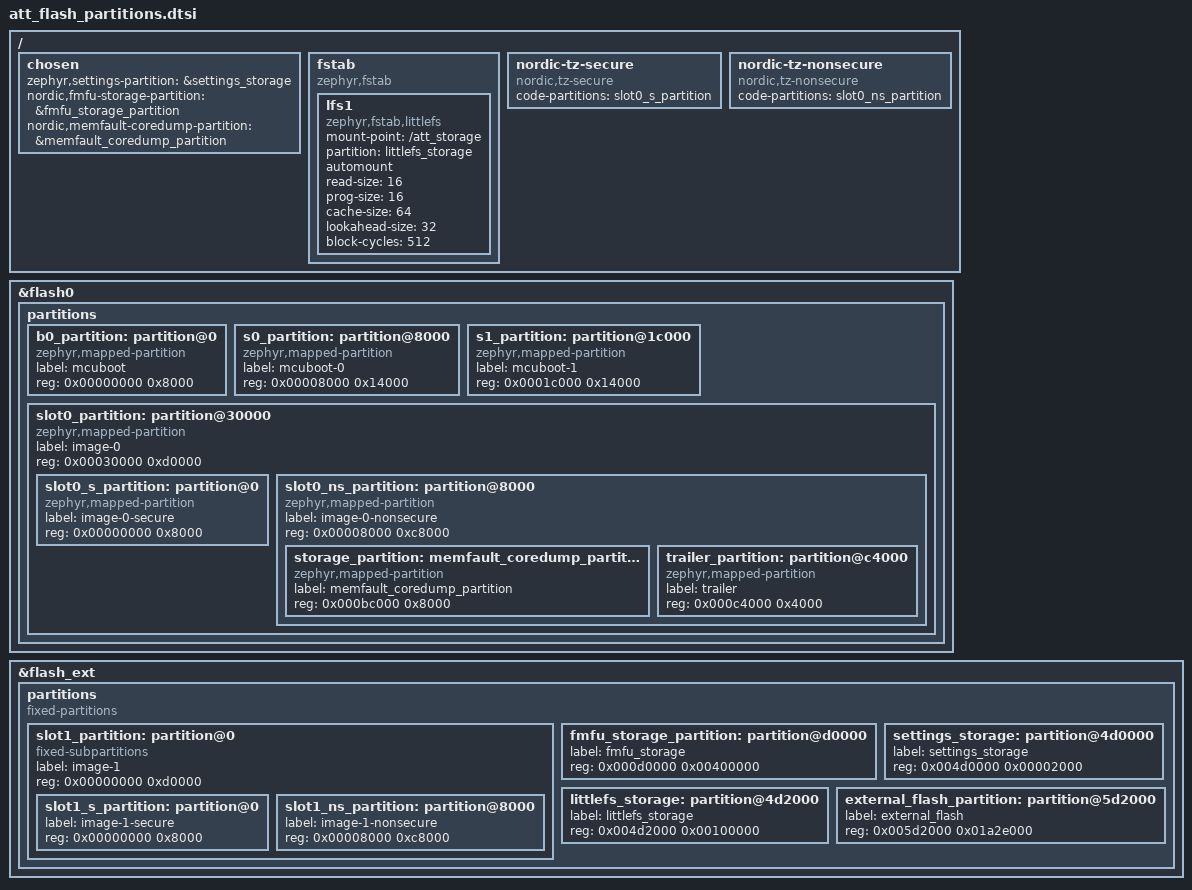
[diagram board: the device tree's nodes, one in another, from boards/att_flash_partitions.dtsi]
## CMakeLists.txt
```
#
# Copyright (c) 2024 Nordic Semiconductor ASA
#
# SPDX-License-Identifier: LicenseRef-Nordic-5-Clause
#

cmake_minimum_required(VERSION 3.20.0)

# Must run before find_package(Zephyr), which reads the Kconfig tree the patches change.
# sysbuild builds apply them earlier, from sysbuild.cmake.
include(${CMAKE_CURRENT_LIST_DIR}/../cmake/apply_sdk_patches.cmake)

find_package(Zephyr REQUIRED HINTS $ENV{ZEPHYR_BASE})
project("Asset Tracker Template")

# Include files that are common for all modules
zephyr_include_directories(src/common)
zephyr_include_directories(memfault/config)

# Add main application source
target_sources(app PRIVATE
	src/main.c
	src/common/app_watchdog.c
)

target_sources_ifdef(CONFIG_APP_NRF9251_HSFLL120_KEEPALIVE app PRIVATE
	src/common/nrf9251_hsfll120_keepalive.c
)

# Module source folders
add_subdirectory(src/modules/network)
add_subdirectory(src/cbor)
add_subdirectory(memfault)

# Optional modules
add_subdirectory_ifdef(CONFIG_APP_BUTTON src/modules/button)
add_subdirectory_ifdef(CONFIG_APP_POWER src/modules/power)
add_subdirectory_ifdef(CONFIG_APP_ENVIRONMENTAL src/modules/environmental)
add_subdirectory_ifdef(CONFIG_APP_LED src/modules/led)
add_subdirectory_ifdef(CONFIG_APP_LOCATION src/modules/location)
add_subdirectory_ifdef(CONFIG_APP_CLOUD src/modules/cloud)
add_subdirectory_ifdef(CONFIG_APP_FOTA src/modules/fota)
add_subdirectory_ifdef(CONFIG_APP_STORAGE src/modules/storage)
add_subdirectory_ifdef(CONFIG_APP_UART_POWER_CONTROL src/modules/uart_power_control)
```

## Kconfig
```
#
# Copyright (c) 2024 Nordic Semiconductor ASA
#
# SPDX-License-Identifier: LicenseRef-Nordic-5-Clause
#

menu "Asset Tracker Template"

rsource "src/Kconfig.main"
rsource "src/modules/power/Kconfig.power"
rsource "src/modules/uart_power_control/Kconfig.uart_power_control"
rsource "src/modules/network/Kconfig.network"
rsource "src/modules/cloud/Kconfig.cloud"
rsource "src/modules/location/Kconfig.location"
rsource "src/modules/led/Kconfig.led"
rsource "src/modules/fota/Kconfig.fota"
rsource "src/modules/environmental/Kconfig.environmental"
rsource "src/modules/button/Kconfig.button"
rsource "src/modules/storage/Kconfig.storage"
rsource "memfault/Kconfig.memfault"

endmenu

menu "Zephyr Kernel"
source "Kconfig.zephyr"
endmenu
```

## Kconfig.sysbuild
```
#
# Copyright (c) 2025 Nordic Semiconductor ASA
#
# SPDX-License-Identifier: LicenseRef-Nordic-5-Clause
#

choice BOOTLOADER
	default BOOTLOADER_MCUBOOT if !BOARD_NATIVE_SIM
endchoice

config NCS_MCUBOOT_LOAD_PERIPHCONF
	default y if BOARD_NRF9251DK_NRF9251_CPUAPP

config SECURE_BOOT_APPCORE
	default y if BOARD_NRF9151DK_NRF9151_NS

# Merge the hex files as a single file for easier flashing with external tools.
config MERGED_HEX_FILES
	default y

# Shared NSIB (b0) signing key for all ATT sysbuild targets. Sysbuild signs images with this
# key; b0 verifies them. Without this, sysbuild autogenerates a new debug key on each pristine
# build. Not for production.
config SECURE_BOOT_SIGNING_KEY_FILE
	default "$(ZEPHYR_NRF_MODULE_DIR)/boards/nordic/thingy91x/nsib_signing_key.pem"

config WIFI_NRF70
	default y if BOARD_THINGY91X_NRF9151_NS

choice WIFI_NRF70_OPER_MODES
	default WIFI_NRF70_SCAN_ONLY if BOARD_THINGY91X_NRF9151_NS
endchoice

source "${ZEPHYR_BASE}/share/sysbuild/Kconfig"
```

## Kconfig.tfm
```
#
# Copyright (c) 2025 Nordic Semiconductor ASA
#
# SPDX-License-Identifier: LicenseRef-Nordic-5-Clause
#

config PM_PARTITION_SIZE_TFM_SRAM
	hex
	default 0x4000
```

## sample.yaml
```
sample:
  name: Asset Tracker Template
  description: Modular, event-driven application framework for nRF91-based asset tracking devices.
tests:
  asset_tracker_template.app:
    sysbuild: true
    build_only: true
    integration_platforms:
      - thingy91x/nrf9151/ns
      - nrf9151dk/nrf9151/ns
      - nrf9251dk/nrf9251/cpuapp
    platform_allow:
      - thingy91x/nrf9151/ns
      - nrf9151dk/nrf9151/ns
      - nrf9251dk/nrf9251/cpuapp
    tags:
      - ci_build
      - sysbuild
```

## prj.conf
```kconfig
#
# Copyright (c) 2024 Nordic Semiconductor ASA
#
# SPDX-License-Identifier: LicenseRef-Nordic-5-Clause
#

CONFIG_NCS_APPLICATION_BOOT_BANNER_STRING="Asset Tracker Template"
CONFIG_NCS_SAMPLES_DEFAULTS=y
CONFIG_WARN_EXPERIMENTAL=n
CONFIG_RESET_ON_FATAL_ERROR=y
CONFIG_LOG_MODE_DEFERRED=y
CONFIG_LOG_BUFFER_SIZE=2048
CONFIG_LOG_PROCESS_THREAD_STACK_SIZE=1280
CONFIG_ZVFS_OPEN_MAX=20
CONFIG_PWM=y

# Heap and stacks
CONFIG_MAIN_STACK_SIZE=2560
# Extended AT host/monitor stack/heap sizes since some nrf_cloud credentials are longer than 1024 bytes.
CONFIG_AT_MONITOR_HEAP_SIZE=2176
CONFIG_HEAP_MEM_POOL_SIZE=12288
CONFIG_HEAP_MEM_POOL_IGNORE_MIN=y
CONFIG_SYSTEM_WORKQUEUE_STACK_SIZE=1408

# Enable Networking
CONFIG_NETWORKING=y
CONFIG_NET_SOCKETS=y
CONFIG_NET_IPV4=y

# Enable Link Controller modules
CONFIG_LTE_LINK_CONTROL=y
CONFIG_LTE_LC_PDN_MODULE=y
CONFIG_LTE_LC_PSM_MODULE=y
CONFIG_LTE_LC_EDRX_MODULE=y
CONFIG_LTE_LC_MODEM_SLEEP_NOTIFICATIONS=y

# Set data profile to ultra-low power
CONFIG_LTE_LC_DATA_PROFILE_MODULE=y
CONFIG_LTE_DATA_PROFILE_INIT_ULTRA_LOW_POWER=y

# Enable PSM (Power Saving Mode)
CONFIG_LTE_LC_WORKQUEUE_STACK_SIZE=2048
CONFIG_LTE_PSM_REQ=y
CONFIG_LTE_PROPRIETARY_PSM_REQ=y
CONFIG_LTE_PSM_REQ_FORMAT_SECONDS=y
# Set Requested TAU to a large value. If the network does not support this value,
# it will typically use the largest supported value. This value should be larger
# than the default update interval (1 hour).
CONFIG_LTE_PSM_REQ_RPTAU_SECONDS=7200

# Set the PSM Requested Active Time to a low number. Since we are constantly polling for
# downlink data, there is no need for prolonged active paging after the RRC connection release.
CONFIG_LTE_PSM_REQ_RAT_SECONDS=6

# Enable eDRX (Extended Discontinuous Reception)
CONFIG_LTE_EDRX_REQ=y
# "0000" is 5.12 s
CONFIG_LTE_EDRX_REQ_VALUE_LTE_M="0000"
CONFIG_LTE_EDRX_REQ_VALUE_NBIOT="0000"

# Modem library
CONFIG_NRF_MODEM_LIB=y
CONFIG_NRF_MODEM_LIB_FAULT_STRERROR=y
CONFIG_NRF_MODEM_LIB_ON_FAULT_APPLICATION_SPECIFIC=y

# Shell
CONFIG_UART_INTERRUPT_DRIVEN=y
CONFIG_SHELL=y
CONFIG_SHELL_WILDCARD=n
CONFIG_SHELL_STACK_SIZE=2560
CONFIG_SHELL_CMD_BUFF_SIZE=2048
CONFIG_SHELL_BACKEND_SERIAL_RX_RING_BUFFER_SIZE=2048
CONFIG_AT_SHELL=y
CONFIG_PM_DEVICE_SHELL=y
# Disable unused shell modules
CONFIG_LTE_SHELL=n
CONFIG_DEVICE_SHELL=n
CONFIG_DATE_SHELL=n
CONFIG_DEVMEM_SHELL=n
CONFIG_APP_VERSION_SHELL=n

# nRF Cloud
CONFIG_NRF_CLOUD=y
CONFIG_NRF_CLOUD_COAP=y
CONFIG_NRF_CLOUD_CHECK_CREDENTIALS=y
CONFIG_NRF_CLOUD_CREDENTIALS_MGMT_MODEM=y
CONFIG_NRF_CLOUD_COAP_MAX_RETRIES=3
CONFIG_NRF_CLOUD_COAP_DISCONNECT_ON_FAILED_REQUEST=y
CONFIG_NRF_CLOUD_COAP_MAX_USER_OPTIONS=2
CONFIG_NRF_CLOUD_PRINT_DETAILS=n
CONFIG_NRF_CLOUD_SEND_SHADOW_INFO_ON_CONNECT=n

# Modem key management and JWT for nRF Cloud authentication
CONFIG_MODEM_KEY_MGMT=y
CONFIG_MODEM_JWT=y

# On initial connection to the cloud, add info sections to the shadow
CONFIG_MODEM_INFO=y
CONFIG_MODEM_INFO_ADD_DEVICE=y
CONFIG_NRF_CLOUD_SEND_DEVICE_STATUS=y
CONFIG_NRF_CLOUD_SEND_DEVICE_INFO_BOOTLOADER_VERSION=y
CONFIG_NRF_CLOUD_SEND_DEVICE_STATUS_NETWORK=y
CONFIG_NRF_CLOUD_SEND_DEVICE_STATUS_SIM=y
CONFIG_NRF_CLOUD_SEND_SERVICE_INFO_FOTA=y

# MCUBOOT - Needed by FOTA
CONFIG_BOOTLOADER_MCUBOOT=y
CONFIG_IMG_MANAGER=y
CONFIG_MCUBOOT_IMG_MANAGER=y

# Date Time lib - Used by PGPS and main application
CONFIG_DATE_TIME=y
CONFIG_DATE_TIME_LOG_LEVEL_ERR=y

CONFIG_SETTINGS=y
CONFIG_SETTINGS_FCB=y
CONFIG_FCB=y

# Downloader - used by FOTAS
CONFIG_DOWNLOADER=y
CONFIG_DOWNLOADER_STACK_SIZE=2000
CONFIG_DOWNLOADER_MAX_FILENAME_SIZE=400
CONFIG_DOWNLOADER_TRANSPORT_HTTP=n
CONFIG_DOWNLOADER_TRANSPORT_COAP=y

# Flash - Used by FOTA
CONFIG_FLASH=y
CONFIG_FLASH_PAGE_LAYOUT=y
CONFIG_FLASH_MAP=y
CONFIG_STREAM_FLASH=y
CONFIG_MPU_ALLOW_FLASH_WRITE=y
CONFIG_NRF_CLOUD_FOTA_POLL=y
CONFIG_NRF_CLOUD_FOTA_DOWNLOAD_FRAGMENT_SIZE=1900
CONFIG_NRF_CLOUD_FOTA_POLL_JOB_CHECK_PROGRESS_THRESHOLD=10
CONFIG_NRF_CLOUD_COAP_DOWNLOADS=y
CONFIG_FOTA_DOWNLOAD=y
CONFIG_FOTA_DOWNLOAD_PROGRESS_EVT=y
CONFIG_FOTA_DL_TIMEOUT_MIN=60
CONFIG_FOTA_SOCKET_RETRIES=5
CONFIG_DFU_TARGET=y

# Memfault
CONFIG_MEMFAULT=y

CONFIG_MEMFAULT_NCS_FW_VERSION_STATIC=y
CONFIG_MEMFAULT_LOGGING_ENABLE=y
CONFIG_MEMFAULT_LOGGING_RAM_SIZE=4096
CONFIG_MEMFAULT_EVENT_STORAGE_SIZE=2048
# Coredump is stored in the dedicated memfault_coredump_partition (32 KiB) that
# lives inside slot0 between the app image and MCUboot's reserved tail. See
# app/boards/att_flash_partitions.dtsi for the layout rationale.
CONFIG_MEMFAULT_NCS_INTERNAL_FLASH_BACKED_COREDUMP=y
CONFIG_MEMFAULT_COREDUMP_STACK_SIZE_TO_COLLECT=1024
CONFIG_MEMFAULT_NCS_POST_COREDUMP_ON_NETWORK_CONNECTED=y

# Upload Memfault data via nRF Cloud CoAP transport.
CONFIG_MEMFAULT_USE_NRF_CLOUD_COAP=y
CONFIG_MEMFAULT_HTTP_ENABLE=n

# Enable a minimal set of Memfault metrics.
CONFIG_MEMFAULT_NCS_LTE_METRICS=y
CONFIG_MEMFAULT_NCS_LOCATION_METRICS=y
CONFIG_MEMFAULT_NCS_STACK_METRICS=n
CONFIG_MEMFAULT_FS_BYTES_FREE_METRIC=n

# Memfault depends on POSIX, disable unneeded POSIX features
CONFIG_POSIX_FILE_SYSTEM=n

# COAP client
# Disable CoAP client retransmissions to rely on nRF Cloud CoAP transport layer retries
# (CONFIG_NRF_CLOUD_COAP_MAX_RETRIES). Multiple retransmission layers scales poorly.
CONFIG_COAP_MAX_RETRANSMIT=1
CONFIG_COAP_INIT_ACK_TIMEOUT_MS=5000
# Set the CoAP client thread to same priority as other modules
CONFIG_COAP_CLIENT_THREAD_PRIORITY=14
CONFIG_COAP_CLIENT_BLOCK_SIZE=1024
CONFIG_COAP_CLIENT_MESSAGE_SIZE=1024
CONFIG_COAP_CLIENT_STACK_SIZE=1280
CONFIG_COAP_EXTENDED_OPTIONS_LEN_VALUE=192
CONFIG_COAP_CLIENT_MAX_PATH_LENGTH=128
CONFIG_COAP_CLIENT_MAX_EXTRA_OPTIONS=3

# Needed for processing floats
CONFIG_PICOLIBC=y
CONFIG_FPU=y

# Zbus
CONFIG_ZBUS=y
CONFIG_ZBUS_MSG_SUBSCRIBER=y
CONFIG_ZBUS_MSG_SUBSCRIBER_NET_BUF_POOL_SIZE=64
CONFIG_ZBUS_CHANNEL_NAME=y

# Zephyr State Machine Framework
CONFIG_SMF=y
CONFIG_SMF_ANCESTOR_SUPPORT=y
CONFIG_SMF_INITIAL_TRANSITION=y

# Location
CONFIG_LOCATION=y
CONFIG_LOCATION_DATA_DETAILS=y
CONFIG_LOCATION_METHOD_GNSS=y
CONFIG_LOCATION_METHOD_CELLULAR=y
CONFIG_LOCATION_SERVICE_EXTERNAL=y
CONFIG_LOCATION_REQUEST_DEFAULT_GNSS_TIMEOUT=60000
CONFIG_LOCATION_REQUEST_DEFAULT_CELLULAR_TIMEOUT=30000
CONFIG_LOCATION_REQUEST_DEFAULT_TIMEOUT=120000
CONFIG_LOCATION_REQUEST_DEFAULT_CELLULAR_CELL_COUNT=3
CONFIG_LOCATION_REQUEST_DEFAULT_GNSS_ACCURACY_LOW=y
CONFIG_LOCATION_REQUEST_DEFAULT_GNSS_VISIBILITY_DETECTION=y
CONFIG_LTE_NETWORK_MODE_LTE_M_NBIOT_GPS=y
CONFIG_NRF_CLOUD_AGNSS=y
# These two must be in sync
CONFIG_APP_LOCATION_NEIGHBOR_CELLS_MAX=8
CONFIG_LTE_NEIGHBOR_CELLS_MAX=8

# Extra Logging
CONFIG_APP_FOTA_LOG_LEVEL_DBG=y
CONFIG_APP_LOCATION_LOG_LEVEL_DBG=y
CONFIG_APP_CLOUD_LOG_LEVEL_DBG=y
CONFIG_APP_NETWORK_LOG_LEVEL_DBG=y
CONFIG_APP_LOG_LEVEL_DBG=y
CONFIG_APP_STORAGE_LOG_LEVEL_DBG=y
CONFIG_APP_BUTTON_LOG_LEVEL_DBG=y

# Task Watchdog
CONFIG_WATCHDOG=y
CONFIG_TASK_WDT=y
CONFIG_TASK_WDT_HW_FALLBACK=y
CONFIG_TASK_WDT_CHANNELS=8
CONFIG_TASK_WDT_MIN_TIMEOUT=10000

# Device power management
CONFIG_PM_DEVICE=y
CONFIG_PM_DEVICE_RUNTIME=n

# nRF Cloud Provisioning
CONFIG_MODEM_ATTEST_TOKEN=y
CONFIG_NRF_PROVISIONING=y
CONFIG_NRF_PROVISIONING_CBOR_RECORDS=5
CONFIG_NRF_PROVISIONING_COAP=y
CONFIG_NRF_PROVISIONING_CODEC=y
CONFIG_NRF_PROVISIONING_CBOR=y
CONFIG_NRF_PROVISIONING_WITH_CERT=y
CONFIG_NRF_PROVISIONING_RX_BUF_SZ=2560
CONFIG_NRF_PROVISIONING_TX_BUF_SZ=2048
CONFIG_NRF_PROVISIONING_STACK_SIZE=3072
CONFIG_NRF_PROVISIONING_CODEC_AT_CMD_LEN=2048
CONFIG_NRF_PROVISIONING_CODEC_RX_SZ_START=1024
```

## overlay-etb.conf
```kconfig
#
# Copyright (c) 2024 Nordic Semiconductor ASA
#
# SPDX-License-Identifier: LicenseRef-Nordic-5-Clause
#

# ETB tracing
CONFIG_ETB_TRACE=y
CONFIG_ETB_TRACE_LOW_POWER=y
CONFIG_ETB_TRACE_LOW_POWER_MIN_IDLE_TIME_MS=1
CONFIG_MEMFAULT_NCS_ETB_CAPTURE=y
# Reduce logging to avoid filling up ETB with data not related to the crash
CONFIG_FAULT_DUMP=0
CONFIG_KERNEL_LOG_LEVEL_OFF=y
```

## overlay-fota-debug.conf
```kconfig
#
# Copyright (c) 2026 Nordic Semiconductor ASA
#
# SPDX-License-Identifier: LicenseRef-Nordic-5-Clause
#

# Debug logging for the FOTA and Memfault OTA path.
# Usage: west build ... -- -DEXTRA_CONF_FILE=overlay-fota-debug.conf

# Memfault SDK (module "mflt", includes the OTA query and override backend)
CONFIG_MEMFAULT_LOG_LEVEL_DBG=y

# nRF Cloud job handling, download and CoAP transport
CONFIG_NRF_CLOUD_FOTA_POLL_LOG_LEVEL_DBG=y
CONFIG_NRF_CLOUD_LOG_LEVEL_DBG=y
CONFIG_NRF_CLOUD_COAP_LOG_LEVEL_DBG=y

# Download and DFU target (image type detection, slot handling)
CONFIG_FOTA_DOWNLOAD_LOG_LEVEL_DBG=y
CONFIG_DFU_TARGET_LOG_LEVEL_DBG=y
CONFIG_DOWNLOADER_LOG_LEVEL_DBG=y

# Log buffering: debug output from the download path is bursty
CONFIG_LOG_BUFFER_SIZE=8192
```

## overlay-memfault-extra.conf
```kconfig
#
# Copyright (c) 2026 Nordic Semiconductor
#
# SPDX-License-Identifier: LicenseRef-Nordic-5-Clause
#

# Enable richer diagnostics for Memfault
CONFIG_MEMFAULT_HEAP_STATS=y
CONFIG_MEMFAULT_EVENT_STORAGE_SIZE=4096
CONFIG_MEMFAULT_LOGGING_RAM_SIZE=3584
CONFIG_PM_PARTITION_SIZE_MEMFAULT_STORAGE=0x2A000
CONFIG_MEMFAULT_COREDUMP_FULL_THREAD_STACKS=y
CONFIG_MEMFAULT_COREDUMP_COLLECT_BSS_REGIONS=y
```

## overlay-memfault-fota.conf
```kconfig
# FOTA support
CONFIG_MEMFAULT_FOTA=y
CONFIG_DOWNLOADER_MAX_FILENAME_SIZE=400
CONFIG_DOWNLOADER_TRANSPORT_COAP=y
CONFIG_NRF_CLOUD_COAP_DOWNLOADS=y
CONFIG_APP_FOTA_TYPE_MEMFAULT=y
```

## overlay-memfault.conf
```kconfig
#
# Copyright (c) 2025 Nordic Semiconductor
#
# SPDX-License-Identifier: LicenseRef-Nordic-5-Clause
#

CONFIG_MEMFAULT=y
CONFIG_MEMFAULT_HEAP_STATS=y
CONFIG_MEMFAULT_LOGGING_ENABLE=y
CONFIG_MEMFAULT_LOGGING_RAM_SIZE=3584
CONFIG_MEMFAULT_FS_BYTES_FREE_METRIC=n
CONFIG_MEMFAULT_COREDUMP_FULL_THREAD_STACKS=y
CONFIG_MEMFAULT_EVENT_STORAGE_SIZE=4096
CONFIG_MEMFAULT_COREDUMP_COLLECT_BSS_REGIONS=y

# Use CoAP for Memfault data transport
CONFIG_MEMFAULT_USE_NRF_CLOUD_COAP=y
CONFIG_MEMFAULT_HTTP_ENABLE=n
CONFIG_NRF_CLOUD_COAP_MAX_USER_OPTIONS=2
CONFIG_COAP_CLIENT_MAX_EXTRA_OPTIONS=3

# Increase max post size to maximum allowable to improve upload efficiency.
# This value is calculated from:
# (COAP_CLIENT_MESSAGE_SIZE + COAP_CLIENT_MESSAGE_HEADER_SIZE - 100B options overhead).
CONFIG_MEMFAULT_COAP_MAX_POST_SIZE=972

# Set max number of messages to send in one batch to max allowable to support
# uploading flash-backed coredumps and modem traces in one upload attempt.
#
# Note: Sending all available data will not block other tasks since upload
# always occurs in a dedicated thread (either via mflt_lte_coredump_thread when
# CONFIG_MEMFAULT_NCS_POST_COREDUMP_ON_NETWORK_CONNECTED is enabled or via
# CONFIG_MEMFAULT_PERIODIC_UPLOAD_USE_DEDICATED_WORKQUEUE which is default y).
CONFIG_MEMFAULT_COAP_MAX_MESSAGES_TO_SEND=10000

# Certificate management - use Zephyr TLS credentials for native TLS on nRF54LM20
# (not modem-offloaded TLS)
CONFIG_MEMFAULT_ROOT_CERT_STORAGE_TLS_CREDENTIAL_STORAGE=y
# Disable modem key management certificate provisioning since we use native TLS
CONFIG_MEMFAULT_NCS_PROVISION_CERTIFICATES=n

# Memfault NCS integration
CONFIG_MEMFAULT_NCS_LTE_METRICS=y
CONFIG_MEMFAULT_NCS_STACK_METRICS=y
CONFIG_MEMFAULT_NCS_POST_COREDUMP_ON_NETWORK_CONNECTED=y
CONFIG_MEMFAULT_NCS_POST_COREDUMP_RETRIES_MAX=10
CONFIG_MEMFAULT_NCS_FW_TYPE="att"

# Ensure Memfault device id matches nRF Cloud client id
CONFIG_MEMFAULT_NCS_DEVICE_ID_HW_ID=y
CONFIG_HW_ID_LIBRARY_SOURCE_UUID=y

# Memfault depends on POSIX, disable unneeded POSIX features
CONFIG_POSIX_FILE_SYSTEM=n
CONFIG_MEMFAULT_LOG_LEVEL_DBG=y
CONFIG_MEMFAULT_NCS_LOG_LEVEL_DBG=y
```

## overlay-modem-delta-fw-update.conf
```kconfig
#
# Copyright (c) 2026 Nordic Semiconductor ASA
#
# SPDX-License-Identifier: LicenseRef-Nordic-5-Clause
#
# Overlay for enabling delta modem FOTA.
# See https://docs.nrfcloud.com/docs/mcu/nrf-modem-fota for full setup instructions.

CONFIG_MEMFAULT_FOTA_MODEM_UPDATE=y
CONFIG_MEMFAULT_FOTA_MODEM_PROJECT_KEY="YOUR_MODEM_PROJECT_KEY"
```

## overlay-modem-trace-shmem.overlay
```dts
/*
 * Copyright (c) 2026 Nordic Semiconductor ASA
 *
 * SPDX-License-Identifier: LicenseRef-Nordic-5-Clause
 */

&sram0_ns_modem {
	reg = <0x0 0x64e8>;
	ranges = <0x0 0x0 0x64e8>;

	cpucell_cpuapp_ipc_shm_trace: sram0_ns_modem@24e8 {
		reg = <0x24e8 0x4000>;
	};
};

/delete-node/ &sram0_ns_app;

&sram0_ns {
	sram0_ns_app: sram0_ns@64e8 {
		reg = <0x64e8 0x37b18>;
	};
};
```

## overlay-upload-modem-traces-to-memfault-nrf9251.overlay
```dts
/*
 * Copyright (c) 2026 Nordic Semiconductor ASA
 *
 * SPDX-License-Identifier: LicenseRef-Nordic-5-Clause
 */

/*
 * nRF9251 counterpart of overlay-upload-modem-traces-to-memfault.overlay. Pair with
 * overlay-upload-modem-traces-to-memfault.conf.
 *
 * The trace UART and shared memory region mirror the nrf92-modem-trace-uart snippet
 * (nrf/snippets/nrf92-modem-trace-uart).
 */

/* Used by the modem_trace dump_uart shell command. */
&uart132 {
	status = "okay";
	current-speed = <1000000>;
	memory-regions = <&cpuapp_dma_region>;
};

/ {
	chosen {
		nordic,modem-trace-uart = &uart132;
	};
};

/delete-node/ &cpuapp_cpucell_ipc_shm_ctrl;
/delete-node/ &cpuapp_cpucell_ipc_shm_heap;
/delete-node/ &cpucell_cpuapp_ipc_shm_heap;

/* Reduce size of application RAM to make room for trace. */
&cpuapp_ram0x_sram {
	reg = <0x2f000000 DT_SIZE_K(332)>;
	ranges = <0x0 0x2f000000 0x53000>;
};

&cpuapp_cpucell_ram0x_region {
	/* Move IPC shared memory and add trace region. */
	cpuapp_cpucell_ipc_shm_ctrl: memory@3000 {
		reg = <0x3000 DT_SIZE_K(4)>;
	};

	cpuapp_cpucell_ipc_shm_heap: memory@4000 {
		reg = <0x4000 DT_SIZE_K(16)>;
	};

	cpucell_cpuapp_ipc_shm_heap: memory@8000 {
		reg = <0x8000 DT_SIZE_K(16)>;
	};

	cpucell_cpuapp_ipc_shm_trace: memory@c000 {
		reg = <0xc000 DT_SIZE_K(16)>;
	};
};

/delete-node/ &external_flash_partition;

&flash_ext {
	partitions {
		modem_trace: partition@500000 {
			label = "modem_trace";
			reg = <0x00500000 0x000ff000>;
		};

		external_flash_partition: partition@5ff000 {
			label = "external_flash";
			reg = <0x005ff000 0x01a01000>;
		};
	};
};
```

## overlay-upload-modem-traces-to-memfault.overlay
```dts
/*
 * Copyright (c) 2026 Nordic Semiconductor ASA
 *
 * SPDX-License-Identifier: LicenseRef-Nordic-5-Clause
 */

&sram0_ns_modem {
	reg = <0x0 0x8800>;
	ranges = <0x0 0x0 0x8800>;

	cpucell_cpuapp_ipc_shm_trace: sram0_ns_modem@4800 {
		reg = <0x4800 0x4000>;
	};
};

/delete-node/ &sram0_ns_app;

&sram0_ns {
	sram0_ns_app: sram0_ns@8800 {
		reg = <0x8800 0x35800>;
	};
};

/delete-node/ &external_flash_partition;

&flash_ext {
	partitions {
		modem_trace: partition@5d2000 {
			label = "modem_trace";
			reg = <0x005d2000 0x000ff000>;
		};

		external_flash_partition: partition@6d1000 {
			label = "external_flash";
			reg = <0x006d1000 0x0192f000>;
		};
	};
};
```

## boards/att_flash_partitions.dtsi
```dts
/*
 * Copyright (c) 2026 Nordic Semiconductor ASA
 *
 * SPDX-License-Identifier: LicenseRef-Nordic-5-Clause
 *
 * Flash layout (flash0, 1 MiB internal):
 * 0x0000_0000  b0_partition                  ( 32 KiB)  immutable bootloader
 * 0x0000_8000  s0_partition                  ( 80 KiB)  primary MCUboot
 * 0x0001_c000  s1_partition                  ( 80 KiB)  secondary MCUboot
 * 0x0003_0000  slot0_partition (image-0)     (832 KiB)
 *   0x0003_0000  slot0_s_partition           ( 32 KiB)  TF-M secure
 *   0x0003_8000  slot0_ns_partition          (800 KiB)  Zephyr/app non-secure
 *     0x000f_4000  memfault_coredump         ( 32 KiB)  coredump (sub-partition)
 *     0x000f_c000  trailer (magic + swap)    ( 16 KiB)  MCUboot swap-status region (sub-partition)
 *
 * Flash layout (flash_ext, 32 MiB external):
 * 0x0000_0000  slot1_partition (image-1)     (832 KiB)  matches slot0 for MCUboot swap-move
 *   0x0000_0000  slot1_s_partition           ( 32 KiB) TF-M secure
 *   0x0000_8000  slot1_ns_partition          (800 KiB) Zephyr/app non-secure
 *   0x000c_8000  ( reserved, unused )        ( 32 KiB) no coredump on secondary
 * 0x000d_0000  fmfu_storage_partition        (  4 MiB) FMFU storage
 * 0x004d_0000  settings_storage              (  8 KiB) Zephyr settings
 * 0x004d_2000  littlefs_storage              (  1 MiB) LittleFS storage
 * 0x005d_2000  external_flash_partition      (~26.2 MiB) free space
 */



/ {
	chosen {
		zephyr,settings-partition = &settings_storage;
		nordic,fmfu-storage-partition = &fmfu_storage_partition;
		nordic,memfault-coredump-partition = &memfault_coredump_partition;
	};

	fstab {
		compatible = "zephyr,fstab";
		lfs1: lfs1 {
			compatible = "zephyr,fstab,littlefs";
			mount-point = "/att_storage";
			partition = <&littlefs_storage>;
			automount;
			read-size = <16>;
			prog-size = <16>;
			cache-size = <64>;
			lookahead-size = <32>;
			block-cycles = <512>;
		};
	};

	/* TrustZone partitioning for this layout. The SoC defaults reference the TF-M
	 * storage partitions, which this layout does not have.
	 */
	/delete-node/ nordic-tz-secure;
	/delete-node/ nordic-tz-nonsecure;

	nordic-tz-secure {
		compatible = "nordic,tz-secure";
		code-partitions = <&slot0_s_partition>;
	};

	nordic-tz-nonsecure {
		compatible = "nordic,tz-nonsecure";
		code-partitions = <&slot0_ns_partition>;
	};
};

/delete-node/ &slot0_partition;

/delete-node/ &storage_partition;

&flash0 {
	partitions {
		ranges;
		#address-cells = <1>;
		#size-cells = <1>;

		b0_partition: partition@0 {
			compatible = "zephyr,mapped-partition";
			label = "mcuboot";
			reg = <0x00000000 0x8000>;
		};

		s0_partition: partition@8000 {
			compatible = "zephyr,mapped-partition";
			label = "mcuboot-0";
			reg = <0x00008000 0x14000>;
		};

		s1_partition: partition@1c000 {
			compatible = "zephyr,mapped-partition";
			label = "mcuboot-1";
			reg = <0x0001c000 0x14000>;
		};

		slot0_partition: partition@30000 {
			compatible = "zephyr,mapped-partition";
			label = "image-0";
			reg = <0x00030000 0xd0000>;
			ranges = <0x0 0x00030000 0xd0000>;
			#address-cells = <1>;
			#size-cells = <1>;

			slot0_s_partition: partition@0 {
				compatible = "zephyr,mapped-partition";
				label = "image-0-secure";
				reg = <0x00000000 0x8000>;
			};

			slot0_ns_partition: partition@8000 {
				compatible = "zephyr,mapped-partition";
				label = "image-0-nonsecure";
				reg = <0x00008000 0xc8000>;
				ranges = <0x0 0x00008000 0xc8000>;
				#address-cells = <1>;
				#size-cells = <1>;

				storage_partition: memfault_coredump_partition: partition@bc000 {
					compatible = "zephyr,mapped-partition";
					label = "memfault_coredump_partition";
					reg = <0x000bc000 0x8000>;
				};

				/*
				 * MCUboot computes its trailer offset from the end of
				 * slot0_partition (flash_area size - boot_trailer_sz()); it
				 * never reads this node. This partition exists purely to mark
				 * that region as reserved in the layout. 16 KiB is reserved for
				   the trailer, actual size may be smaller (typically ~ 6 KiB).
				 */
				trailer_partition: partition@c4000 {
					compatible = "zephyr,mapped-partition";
					label = "trailer";
					reg = <0x000c4000 0x4000>;
				};
			};
		};
	};
};

&flash_ext {
	status = "okay";

	partitions {
		compatible = "fixed-partitions";
		#address-cells = <1>;
		#size-cells = <1>;

		slot1_partition: partition@0 {
			compatible = "fixed-subpartitions";
			label = "image-1";
			reg = <0x00000000 0xd0000>;
			ranges = <0x0 0x00000 0xd0000>;
			#address-cells = <1>;
			#size-cells = <1>;

			slot1_s_partition: partition@0 {
				label = "image-1-secure";
				reg = <0x00000000 0x8000>;
			};

			slot1_ns_partition: partition@8000 {
				label = "image-1-nonsecure";
				reg = <0x00008000 0xc8000>;
			};
		};

		fmfu_storage_partition: partition@d0000 {
			label = "fmfu_storage";
			reg = <0x000d0000 0x00400000>;
		};

		settings_storage: partition@4d0000 {
			label = "settings_storage";
			reg = <0x004d0000 0x00002000>;
		};

		littlefs_storage: partition@4d2000 {
			label = "littlefs_storage";
			reg = <0x004d2000 0x00100000>;
		};

		external_flash_partition: partition@5d2000 {
			label = "external_flash";
			reg = <0x005d2000 0x01a2e000>;
		};
	};
};
```

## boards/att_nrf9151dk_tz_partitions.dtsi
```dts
/*
 * Copyright (c) 2026 Nordic Semiconductor ASA
 *
 * SPDX-License-Identifier: LicenseRef-Nordic-5-Clause
 *
 * nrf9151dk-only fixup: unlike thingy91x, which has its own board-specific
 * partition file with a from-scratch nordic-tz-secure/nordic-tz-nonsecure
 * definition, nrf9151dk falls back to the generic nrf91xx_partition.dtsi.
 * Its nordic-tz-secure node's data-partitions property references
 * tfm_ps_partition/tfm_its_partition/tfm_otp_partition, which the nrf9151dk
 * board overlays delete (this layout doesn't use TF-M storage). Delete and
 * recreate nordic-tz-secure/nordic-tz-nonsecure without the now-dangling
 * references, matching the pattern Nordic's own updated sample partition
 * files (e.g. nrf91_bootloader_partitions.dtsi) use for the same situation.
 *
 * This is deliberately kept out of att_flash_partitions.dtsi (shared with
 * thingy91x): thingy91x's own nordic-tz-secure/nordic-tz-nonsecure
 * deliberately excludes slot1 (external flash, outside TF-M's purview), and
 * this file's slot1_s_partition/slot1_ns_partition inclusion would silently
 * override that.
 */
/ {
	/delete-node/ nordic-tz-secure;
	/delete-node/ nordic-tz-nonsecure;

	nordic-tz-secure {
		compatible = "nordic,tz-secure";
		code-partitions = <&slot0_s_partition>,
				  <&slot1_s_partition>;
	};

	nordic-tz-nonsecure {
		compatible = "nordic,tz-nonsecure";
		code-partitions = <&slot0_ns_partition>,
				  <&slot1_ns_partition>;
		data-partitions = <&storage_partition>;
	};
};
```

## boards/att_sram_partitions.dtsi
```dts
/*
 * Copyright (c) 2026 Nordic Semiconductor ASA
 *
 * SPDX-License-Identifier: LicenseRef-Nordic-5-Clause
 *
 * SRAM layout (256 KiB total):
 *
 *    0x2000_0000  Secure RAM                    (    8 KiB)
 *    0x2000_2000  Non-secure RAM                (  248 KiB)
 *      0x2000_2000  Modem shared area           (  9416 B)
 *        0x2000_2000  control                   (  1256 B)
 *        0x2000_24e8  app -> cell               (  4096 B)
 *        0x2000_34e8  cell -> app               (  4096 B)
 *      0x2000_44e8  Application RAM             (~238.8 KiB)
 */

/delete-node/ &sram0_s;
/delete-node/ &sram0_ns;

&sram0 {
	sram0_s: sram@0 {
		reg = <0x0 0x2000>;
	};

	sram0_ns: sram@2000 {
		reg = <0x2000 0x3e000>;
		#address-cells = <1>;
		#size-cells = <1>;
		ranges = <0x0 0x2000 0x3e000>;

		/* Must be in first 128 kB of RAM. */
		sram0_ns_modem: sram0_ns@0 {
			reg = <0x0 0x24e8>;
			#address-cells = <1>;
			#size-cells = <1>;
			ranges = <0x0 0x0 0x24e8>;

			cpuapp_cpucell_ipc_shm_ctrl: sram0_ns_modem@0 {
				/* NRF_MODEM_SHMEM_CTRL_SIZE for nRF91 cellular */
				reg = <0x0 0x4e8>;
			};

			cpuapp_cpucell_ipc_shm_heap: sram0_ns_modem@4e8 {
				/* Modem library TX buffer, 4 KiB is sufficient */
				reg = <0x4e8 0x1000>;
			};

			cpucell_cpuapp_ipc_shm_heap: sram0_ns_modem@14e8 {
				/* Modem library RX buffer, 4 KiB is sufficient */
				reg = <0x14e8 0x1000>;
			};
		};

		sram0_ns_app: sram0_ns@24e8 {
			reg = <0x24e8 0x3bb18>;
		};
	};
};
```

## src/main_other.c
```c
/*
 * Copyright (c) 2024 Nordic Semiconductor ASA
 *
 * SPDX-License-Identifier: LicenseRef-Nordic-5-Clause
 */

#include <stdint.h>
#include <zephyr/logging/log.h>

/* Register log module */
LOG_MODULE_REGISTER(main, 4);

int main(void)
{
	LOG_DBG("Starting application");
}
```
